###############################################################
#  Generated by:      Cadence Innovus 20.13-s083_1
#  OS:                Linux x86_64(Host ID caddy13)
#  Generated on:      Mon Jul 19 16:43:34 2021
#  Design:            sar_adc_controller
#  Command:           write_lef_abstract -specifyTopLayer 6 -PGPinLayers {5 6} -noCutObs -stripePin results/sar_adc_controller.lef
###############################################################

VERSION 5.8 ;

BUSBITCHARS "[]" ;
DIVIDERCHAR "/" ;

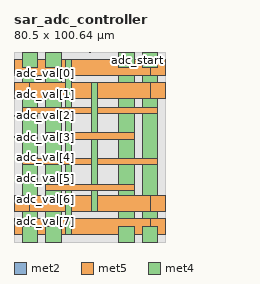
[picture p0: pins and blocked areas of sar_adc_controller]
MACRO sar_adc_controller
  CLASS BLOCK ;
  SIZE 80.500000 BY 100.640000 ;
  FOREIGN sar_adc_controller 0.000000 0.000000 ;
  ORIGIN 0 0 ;
  SYMMETRY X Y R90 ;
  PIN clk
    DIRECTION INPUT ;
    USE SIGNAL ;
    ANTENNAPARTIALMETALAREA 5.3802 LAYER met2  ;
    ANTENNAPARTIALMETALSIDEAREA 26.74 LAYER met2  ;
    ANTENNAPARTIALCUTAREA 0.04 LAYER via2  ;
    ANTENNAPARTIALMETALAREA 11.4156 LAYER met3  ;
    ANTENNAPARTIALMETALSIDEAREA 61.824 LAYER met3  ;
    ANTENNAMODEL OXIDE1 ;
    ANTENNAGATEAREA 0.9825 LAYER met3  ;
    ANTENNAMAXAREACAR 14.4443 LAYER met3  ;
    ANTENNAMAXSIDEAREACAR 74.5771 LAYER met3  ;
    ANTENNAMAXCUTCAR 0.228125 LAYER via3  ;
    PORT
      LAYER met2 ;
        RECT 1.080000 100.155000 1.220000 100.640000 ;
    END
  END clk
  PIN rst_n
    DIRECTION INPUT ;
    USE SIGNAL ;
    ANTENNAPARTIALMETALAREA 9.8095 LAYER met2  ;
    ANTENNAPARTIALMETALSIDEAREA 48.0025 LAYER met2  ;
    ANTENNAMODEL OXIDE1 ;
    ANTENNAGATEAREA 1.503 LAYER met2  ;
    ANTENNAMAXAREACAR 25.6 LAYER met2  ;
    ANTENNAMAXSIDEAREACAR 120.2 LAYER met2  ;
    ANTENNAPARTIALCUTAREA 0.04 LAYER via2  ;
    ANTENNAMAXCUTCAR 0.613121 LAYER via2  ;
    ANTENNAPARTIALMETALAREA 1.6368 LAYER met3  ;
    ANTENNAPARTIALMETALSIDEAREA 9.2 LAYER met3  ;
    ANTENNAGATEAREA 2.889 LAYER met3  ;
    ANTENNAMAXAREACAR 26.1666 LAYER met3  ;
    ANTENNAMAXSIDEAREACAR 123.384 LAYER met3  ;
    ANTENNAMAXCUTCAR 0.615368 LAYER via3  ;
    PORT
      LAYER met2 ;
        RECT 40.180000 100.155000 40.320000 100.640000 ;
    END
  END rst_n
  PIN adc_start
    DIRECTION INPUT ;
    USE SIGNAL ;
    ANTENNAPARTIALMETALAREA 5.1169 LAYER met2  ;
    ANTENNAPARTIALMETALSIDEAREA 25.4765 LAYER met2  ;
    ANTENNAMODEL OXIDE1 ;
    ANTENNAGATEAREA 0.2475 LAYER met2  ;
    ANTENNAMAXAREACAR 37.6333 LAYER met2  ;
    ANTENNAMAXSIDEAREACAR 185.956 LAYER met2  ;
    ANTENNAMAXCUTCAR 0.207677 LAYER via2  ;
    PORT
      LAYER met2 ;
        RECT 79.280000 100.155000 79.420000 100.640000 ;
    END
  END adc_start
  PIN comparator_val
    DIRECTION INPUT ;
    USE SIGNAL ;
    ANTENNAPARTIALMETALAREA 1.5784 LAYER met2  ;
    ANTENNAPARTIALMETALSIDEAREA 7.784 LAYER met2  ;
    ANTENNAMODEL OXIDE1 ;
    ANTENNAGATEAREA 0.2475 LAYER met2  ;
    ANTENNAMAXAREACAR 26.1226 LAYER met2  ;
    ANTENNAMAXSIDEAREACAR 128.495 LAYER met2  ;
    ANTENNAMAXCUTCAR 0.207677 LAYER via2  ;
    PORT
      LAYER met2 ;
        RECT 0.000000 100.400000 0.485000 100.540000 ;
    END
  END comparator_val
  PIN run_adc_n
    DIRECTION OUTPUT ;
    USE SIGNAL ;
    ANTENNADIFFAREA 0.429 LAYER met2  ;
    ANTENNAPARTIALMETALAREA 0.1028 LAYER met2  ;
    ANTENNAPARTIALMETALSIDEAREA 0.406 LAYER met2  ;
    PORT
      LAYER met2 ;
        RECT 0.000000 0.100000 0.485000 0.240000 ;
    END
  END run_adc_n
  PIN adc_val[7]
    DIRECTION OUTPUT ;
    USE SIGNAL ;
    ANTENNADIFFAREA 0.336 LAYER met2  ;
    ANTENNAPARTIALMETALAREA 2.9007 LAYER met2  ;
    ANTENNAPARTIALMETALSIDEAREA 14.3955 LAYER met2  ;
    PORT
      LAYER met2 ;
        RECT 0.000000 10.980000 0.485000 11.120000 ;
    END
  END adc_val[7]
  PIN adc_val[6]
    DIRECTION OUTPUT ;
    USE SIGNAL ;
    ANTENNADIFFAREA 0.336 LAYER met2  ;
    ANTENNAPARTIALMETALAREA 1.003 LAYER met2  ;
    ANTENNAPARTIALMETALSIDEAREA 4.907 LAYER met2  ;
    PORT
      LAYER met2 ;
        RECT 0.000000 22.200000 0.485000 22.340000 ;
    END
  END adc_val[6]
  PIN adc_val[5]
    DIRECTION OUTPUT ;
    USE SIGNAL ;
    ANTENNADIFFAREA 0.336 LAYER met2  ;
    ANTENNAPARTIALMETALAREA 0.0937 LAYER met2  ;
    ANTENNAPARTIALMETALSIDEAREA 0.3605 LAYER met2  ;
    PORT
      LAYER met2 ;
        RECT 0.000000 33.420000 0.485000 33.560000 ;
    END
  END adc_val[5]
  PIN adc_val[4]
    DIRECTION OUTPUT ;
    USE SIGNAL ;
    ANTENNADIFFAREA 0.336 LAYER met2  ;
    ANTENNAPARTIALMETALAREA 0.1938 LAYER met2  ;
    ANTENNAPARTIALMETALSIDEAREA 0.861 LAYER met2  ;
    PORT
      LAYER met2 ;
        RECT 0.000000 44.640000 0.485000 44.780000 ;
    END
  END adc_val[4]
  PIN adc_val[3]
    DIRECTION OUTPUT ;
    USE SIGNAL ;
    ANTENNADIFFAREA 0.336 LAYER met2  ;
    ANTENNAPARTIALMETALAREA 1.5308 LAYER met2  ;
    ANTENNAPARTIALMETALSIDEAREA 7.546 LAYER met2  ;
    PORT
      LAYER met2 ;
        RECT 0.000000 55.520000 0.485000 55.660000 ;
    END
  END adc_val[3]
  PIN adc_val[2]
    DIRECTION OUTPUT ;
    USE SIGNAL ;
    ANTENNADIFFAREA 0.336 LAYER met2  ;
    ANTENNAPARTIALMETALAREA 0.2414 LAYER met2  ;
    ANTENNAPARTIALMETALSIDEAREA 1.099 LAYER met2  ;
    PORT
      LAYER met2 ;
        RECT 0.000000 66.740000 0.485000 66.880000 ;
    END
  END adc_val[2]
  PIN adc_val[1]
    DIRECTION OUTPUT ;
    USE SIGNAL ;
    ANTENNADIFFAREA 0.336 LAYER met2  ;
    ANTENNAPARTIALMETALAREA 1.3362 LAYER met2  ;
    ANTENNAPARTIALMETALSIDEAREA 6.573 LAYER met2  ;
    PORT
      LAYER met2 ;
        RECT 0.000000 77.960000 0.485000 78.100000 ;
    END
  END adc_val[1]
  PIN adc_val[0]
    DIRECTION OUTPUT ;
    USE SIGNAL ;
    ANTENNADIFFAREA 0.336 LAYER met2  ;
    ANTENNAPARTIALMETALAREA 0.6222 LAYER met2  ;
    ANTENNAPARTIALMETALSIDEAREA 3.003 LAYER met2  ;
    PORT
      LAYER met2 ;
        RECT 0.000000 89.180000 0.485000 89.320000 ;
    END
  END adc_val[0]
  PIN out_valid
    DIRECTION OUTPUT ;
    USE SIGNAL ;
    ANTENNADIFFAREA 0.429 LAYER met2  ;
    ANTENNAPARTIALMETALAREA 4.5443 LAYER met2  ;
    ANTENNAPARTIALMETALSIDEAREA 22.6135 LAYER met2  ;
    PORT
      LAYER met2 ;
        RECT 80.015000 100.400000 80.500000 100.540000 ;
    END
  END out_valid
  PIN VSS
    DIRECTION INOUT ;
    USE GROUND ;
    PORT
      LAYER met5 ;
        RECT 72.340000 88.400000 80.500000 96.560000 ;
    END
    PORT
      LAYER met5 ;
        RECT 0.000000 88.400000 8.160000 96.560000 ;
    END
    PORT
      LAYER met5 ;
        RECT 72.340000 4.080000 80.500000 12.240000 ;
    END
    PORT
      LAYER met5 ;
        RECT 0.000000 4.080000 8.160000 12.240000 ;
    END
    PORT
      LAYER met4 ;
        RECT 67.840000 92.480000 76.000000 100.640000 ;
    END
    PORT
      LAYER met4 ;
        RECT 67.840000 0.000000 76.000000 8.160000 ;
    END
    PORT
      LAYER met4 ;
        RECT 4.500000 92.480000 12.660000 100.640000 ;
    END
    PORT
      LAYER met4 ;
        RECT 4.500000 0.000000 12.660000 8.160000 ;
    END

# P/G power stripe data as pin
    PORT
      LAYER met4 ;
        RECT 27.200000 4.080000 30.560000 96.560000 ;
        RECT 67.840000 0.000000 76.000000 100.640000 ;
        RECT 4.500000 0.000000 12.660000 100.640000 ;
      LAYER met5 ;
        RECT 0.000000 4.080000 80.500000 12.240000 ;
        RECT 4.500000 40.800000 76.000000 44.160000 ;
        RECT 0.000000 88.400000 80.500000 96.560000 ;
        RECT 4.500000 68.000000 76.000000 71.360000 ;
    END
# end of P/G power stripe data as pin

  END VSS
  PIN VDD
    DIRECTION INOUT ;
    USE POWER ;
    PORT
      LAYER met5 ;
        RECT 72.340000 76.160000 80.500000 84.320000 ;
    END
    PORT
      LAYER met5 ;
        RECT 0.000000 76.160000 8.160000 84.320000 ;
    END
    PORT
      LAYER met5 ;
        RECT 72.340000 16.320000 80.500000 24.480000 ;
    END
    PORT
      LAYER met5 ;
        RECT 0.000000 16.320000 8.160000 24.480000 ;
    END
    PORT
      LAYER met4 ;
        RECT 55.600000 92.480000 63.760000 100.640000 ;
    END
    PORT
      LAYER met4 ;
        RECT 55.600000 0.000000 63.760000 8.160000 ;
    END
    PORT
      LAYER met4 ;
        RECT 16.740000 92.480000 24.900000 100.640000 ;
    END
    PORT
      LAYER met4 ;
        RECT 16.740000 0.000000 24.900000 8.160000 ;
    END

# P/G power stripe data as pin
    PORT
      LAYER met4 ;
        RECT 40.800000 16.320000 44.160000 84.320000 ;
        RECT 55.600000 0.000000 63.760000 100.640000 ;
        RECT 16.740000 0.000000 24.900000 100.640000 ;
      LAYER met5 ;
        RECT 16.740000 27.200000 63.760000 30.560000 ;
        RECT 0.000000 16.320000 80.500000 24.480000 ;
        RECT 16.740000 54.400000 63.760000 57.760000 ;
        RECT 0.000000 76.160000 80.500000 84.320000 ;
    END
# end of P/G power stripe data as pin

  END VDD
  OBS
    LAYER li1 ;
      RECT 0.000000 0.000000 80.500000 100.640000 ;
    LAYER met1 ;
      RECT 0.000000 0.000000 80.500000 100.640000 ;
    LAYER met2 ;
      RECT 0.000000 0.000000 80.500000 100.640000 ;
    LAYER met3 ;
      RECT 0.000000 0.000000 80.500000 100.640000 ;
    LAYER met4 ;
      RECT 0.000000 0.000000 80.500000 100.640000 ;
    LAYER met5 ;
      RECT 0.000000 0.000000 80.500000 100.640000 ;
  END
END sar_adc_controller

END LIBRARY
